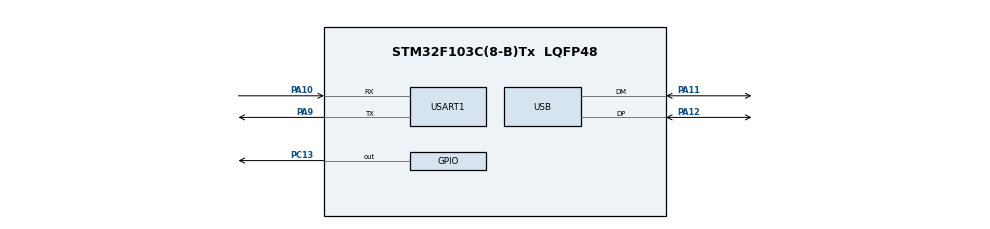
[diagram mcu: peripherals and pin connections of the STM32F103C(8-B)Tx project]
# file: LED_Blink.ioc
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Mcu.Family=STM32F1
Mcu.Name=STM32F103C(8-B)Tx
Mcu.Package=LQFP48
NVIC.PriorityGroup=NVIC_PRIORITYGROUP_4
NVIC.USB_LP_CAN1_RX0_IRQn=true\:0\:0\:false\:false\:true\:false\:true\:true
PA10.Mode=Asynchronous
PA10.Signal=USART1_RX
PA11.Mode=Device
PA11.Signal=USB_DM
PA12.Mode=Device
PA12.Signal=USB_DP
PA13.Mode=Serial_Wire
PA13.Signal=SYS_JTMS-SWDIO
PA14.Mode=Serial_Wire
PA14.Signal=SYS_JTCK-SWCLK
PA9.Mode=Asynchronous
PA9.Signal=USART1_TX
PC13-TAMPER-RTC.Signal=GPIO_Output
PD0-OSC_IN.Mode=HSE-External-Oscillator
PD0-OSC_IN.Signal=RCC_OSC_IN
PD1-OSC_OUT.Mode=HSE-External-Oscillator
PD1-OSC_OUT.Signal=RCC_OSC_OUT
ProjectManager.HeapSize=0x200
ProjectManager.StackSize=0x400
ProjectManager.TargetToolchain=MDK-ARM V5.32
RCC.AHBFreq_Value=72000000
RCC.APB1CLKDivider=RCC_HCLK_DIV2
RCC.APB1Freq_Value=36000000
RCC.APB1TimFreq_Value=72000000
RCC.APB2Freq_Value=72000000
RCC.APB2TimFreq_Value=72000000
RCC.HCLKFreq_Value=72000000
RCC.PLLMUL=RCC_PLL_MUL9
RCC.PLLSourceVirtual=RCC_PLLSOURCE_HSE
RCC.SYSCLKFreq_VALUE=72000000
RCC.SYSCLKSource=RCC_SYSCLKSOURCE_PLLCLK
RCC.USBFreq_Value=48000000
RCC.USBPrescaler=RCC_USBCLKSOURCE_PLL_DIV1_5
USART1.VirtualMode=VM_ASYNC
USB_DEVICE.CLASS_NAME_FS=CDC
USB_DEVICE.VirtualMode=Cdc
USB_DEVICE.VirtualModeFS=Cdc_FS
VP_USB_DEVICE_VS_USB_DEVICE_CDC_FS.Mode=CDC_FS
board=custom

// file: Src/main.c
/* USER CODE BEGIN Header */
/**
  ******************************************************************************
  * @file           : main.c
  * @brief          : Main program body
  ******************************************************************************
  * @attention
  *
  * Copyright (c) 2026 STMicroelectronics.
  * All rights reserved.
  *
  * This software is licensed under terms that can be found in the LICENSE file
  * in the root directory of this software component.
  * If no LICENSE file comes with this software, it is provided AS-IS.
  *
  ******************************************************************************
  */
/* USER CODE END Header */
#include "main.h"
#include "usart.h"
#include "gpio.h"

/* USER CODE BEGIN Includes */
#include <stdio.h>
#include <string.h>
/* USER CODE END Includes */

/* USER CODE BEGIN PV */
// ????????
typedef enum {
    IDLE = 0,
    FEED,
    PROCESS,
    CHECK,
    SORT
} StateTypeDef;

// ???????
StateTypeDef currentState = IDLE;       // ????
uint32_t stateStartTime = 0;            // ????????????
uint32_t lastLedToggleTime = 0;         // ??LED??????
uint32_t ledInterval = 500;             // LED????(??),??500ms
/* USER CODE END PV */

void SystemClock_Config(void);

/* USER CODE BEGIN 0 */
// ??JSON???????
void SendStateJson(StateTypeDef state, uint32_t tick)
{
    char jsonBuffer[64];
    const char* stateNames[] = {"IDLE", "FEED", "PROCESS", "CHECK", "SORT"};
    int len = snprintf(jsonBuffer, sizeof(jsonBuffer),
                       "{\"state\":\"%s\",\"tick\":%lu}\r\n",
                       stateNames[state], tick);
    HAL_UART_Transmit(&huart1, (uint8_t*)jsonBuffer, len, HAL_MAX_DELAY);
}

// ??????LED????
void SetLedInterval(StateTypeDef state)
{
    switch(state)
    {
        case IDLE:    ledInterval = 500;  break;  // ?? 1Hz
        case FEED:    ledInterval = 250;  break;  // 2Hz
        case PROCESS: ledInterval = 100;  break;  // 5Hz
        case CHECK:   ledInterval = 50;   break;  // 10Hz
        case SORT:    ledInterval = 25;   break;  // 20Hz
        default:      ledInterval = 500;  break;
    }
}
/* USER CODE END 0 */

int main(void)
{

  /* MCU Configuration--------------------------------------------------------*/

  /* Reset of all peripherals, Initializes the Flash interface and the Systick. */
  HAL_Init();

  /* Configure the system clock */
  SystemClock_Config();

  /* Initialize all configured peripherals */
  MX_GPIO_Init();
  MX_USART1_UART_Init();

  /* Infinite loop */
  /* USER CODE BEGIN WHILE */
  while (1)
  {
    uint32_t currentTick = HAL_GetTick();  // ????????(??)

    // ---- 1. ?????(?2?????) ----
    if (currentTick - stateStartTime >= 2000)
    {
        stateStartTime = currentTick;  // ??????

        // ????????JSON
        SendStateJson(currentState, currentTick);

        // ???????LED????
        SetLedInterval(currentState);

        // ??????
        currentState++;
        if (currentState > SORT)
        {
            currentState = IDLE;
        }
    }

    // ---- 2. LED????(???) ----
    if (currentTick - lastLedToggleTime >= ledInterval)
    {
        lastLedToggleTime = currentTick;
        HAL_GPIO_TogglePin(GPIOC, GPIO_PIN_13);  // ??PC13(LED)
    }

    /* USER CODE END WHILE */

  }
}

void SystemClock_Config(void)
{
  RCC_OscInitTypeDef RCC_OscInitStruct = {0};
  RCC_ClkInitTypeDef RCC_ClkInitStruct = {0};

  /** Initializes the RCC Oscillators according to the specified parameters
  * in the RCC_OscInitTypeDef structure.
  */
  RCC_OscInitStruct.OscillatorType = RCC_OSCILLATORTYPE_HSI;
  RCC_OscInitStruct.HSIState = RCC_HSI_ON;
  RCC_OscInitStruct.HSICalibrationValue = RCC_HSICALIBRATION_DEFAULT;
  RCC_OscInitStruct.PLL.PLLState = RCC_PLL_NONE;
  if (HAL_RCC_OscConfig(&RCC_OscInitStruct) != HAL_OK)
  {
    Error_Handler();
  }

  /** Initializes the CPU, AHB and APB buses clocks
  */
  RCC_ClkInitStruct.ClockType = RCC_CLOCKTYPE_HCLK|RCC_CLOCKTYPE_SYSCLK
                              |RCC_CLOCKTYPE_PCLK1|RCC_CLOCKTYPE_PCLK2;
  RCC_ClkInitStruct.SYSCLKSource = RCC_SYSCLKSOURCE_HSI;
  RCC_ClkInitStruct.AHBCLKDivider = RCC_SYSCLK_DIV1;
  RCC_ClkInitStruct.APB1CLKDivider = RCC_HCLK_DIV1;
  RCC_ClkInitStruct.APB2CLKDivider = RCC_HCLK_DIV1;

  if (HAL_RCC_ClockConfig(&RCC_ClkInitStruct, FLASH_LATENCY_0) != HAL_OK)
  {
    Error_Handler();
  }
}

void Error_Handler(void)
{
  __disable_irq();
  while (1)
  {
  }
}
